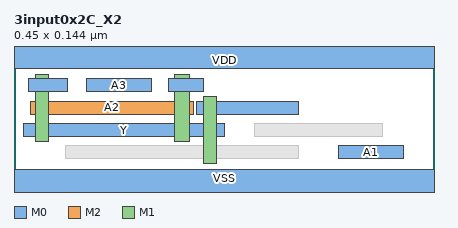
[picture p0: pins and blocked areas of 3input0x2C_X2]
MACRO 3input0x2C_X2
  CLASS CORE ;
  ORIGIN 0 0 ;
  FOREIGN 3input0x2C_X2 0 0 ;
  SIZE 0.4500 BY 0.1440 ;
  SYMMETRY X Y ;
  SITE coresite ;
  PIN A1
    DIRECTION INPUT ;
    USE SIGNAL ;
    PORT
      LAYER M0 ;
        RECT 0.3480 0.0290 0.4170 0.0430 ;
    END
  END A1
  PIN A2
    DIRECTION INPUT ;
    USE SIGNAL ;
    PORT
      LAYER M2 ;
        RECT 0.0180 0.0770 0.1920 0.0910 ;
      LAYER M1 ;
        RECT 0.0225 0.0480 0.0375 0.1200 ;
        RECT 0.1725 0.0480 0.1875 0.1200 ;
      LAYER M0 ;
        RECT 0.1650 0.1010 0.2025 0.1150 ;
        RECT 0.0150 0.1010 0.0570 0.1150 ;
    END
  END A2
  PIN A3
    DIRECTION INPUT ;
    USE SIGNAL ;
    PORT
      LAYER M0 ;
        RECT 0.0780 0.1010 0.1470 0.1150 ;
    END
  END A3
  PIN Y
    DIRECTION OUTPUT ;
    USE SIGNAL ;
    PORT
      LAYER M1 ;
        RECT 0.2025 0.0240 0.2175 0.0960 ;
      LAYER M0 ;
        RECT 0.1950 0.0770 0.3045 0.0910 ;
        RECT 0.0105 0.0530 0.2250 0.0670 ;
    END
  END Y
  PIN VDD
    DIRECTION INOUT ;
    USE POWER ;
    SHAPE ABUTMENT ;
    PORT
      LAYER M0 ;
        RECT 0.0000 0.1260 0.4500 0.1620 ;
    END
  END VDD
  PIN VSS
    DIRECTION INOUT ;
    USE GROUND ;
    SHAPE ABUTMENT ;
    PORT
      LAYER M0 ;
        RECT 0.0000 -0.0180 0.4500 0.0180 ;
    END
  END VSS
  OBS
    LAYER V1 ;
      RECT 0.0230 0.0770 0.0370 0.0910 ;
      RECT 0.1730 0.0770 0.1870 0.0910 ;
    LAYER V0 ;
      RECT 0.2030 0.0770 0.2170 0.0910 ;
      RECT 0.2030 0.0530 0.2170 0.0670 ;
      RECT 0.0230 0.1010 0.0370 0.1150 ;
      RECT 0.1730 0.1010 0.1870 0.1150 ;
    LAYER M0 ;
      RECT 0.0555 0.0290 0.3045 0.0430 ;
      RECT 0.2580 0.0530 0.3945 0.0670 ;
      RECT 0.0555 0.0770 0.1695 0.0910 ;
  END
END 3input0x2C_X2
